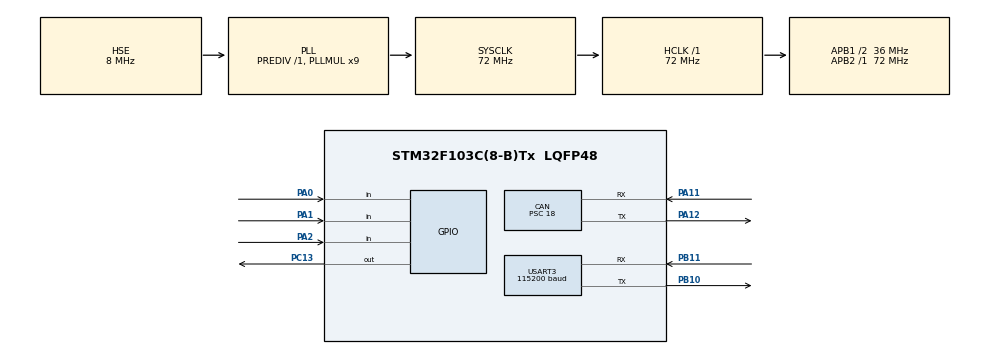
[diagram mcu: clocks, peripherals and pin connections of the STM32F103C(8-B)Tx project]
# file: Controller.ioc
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CAN.BS1=CAN_BS1_2TQ
CAN.CalculateBaudRate=500000
CAN.CalculateTimeBit=2000
CAN.CalculateTimeQuantum=500.0
CAN.Prescaler=18
Mcu.Family=STM32F1
Mcu.Name=STM32F103C(8-B)Tx
Mcu.Package=LQFP48
NVIC.CAN1_RX1_IRQn=true\:2\:0\:true\:false\:true\:true\:true\:true
NVIC.PriorityGroup=NVIC_PRIORITYGROUP_4
NVIC.TIM3_IRQn=true\:1\:0\:true\:false\:true\:true\:true\:true
NVIC.USART3_IRQn=true\:0\:0\:true\:false\:true\:true\:true\:true
NVIC.USB_LP_CAN1_RX0_IRQn=true\:2\:0\:true\:false\:true\:true\:true\:true
PA0-WKUP.GPIO_PuPd=GPIO_PULLUP
PA0-WKUP.Signal=GPIO_Input
PA1.GPIO_PuPd=GPIO_PULLUP
PA1.Signal=GPIO_Input
PA11.Mode=CAN_Activate
PA11.Signal=CAN_RX
PA12.Mode=CAN_Activate
PA12.Signal=CAN_TX
PA13.Mode=Serial_Wire
PA13.Signal=SYS_JTMS-SWDIO
PA14.Mode=Serial_Wire
PA14.Signal=SYS_JTCK-SWCLK
PA2.Signal=GPIO_Input
PB10.Mode=Asynchronous
PB10.Signal=USART3_TX
PB11.Mode=Asynchronous
PB11.Signal=USART3_RX
PC13-TAMPER-RTC.GPIO_PuPd=GPIO_PULLUP
PC13-TAMPER-RTC.Signal=GPIO_Output
PC14-OSC32_IN.Mode=LSE-External-Oscillator
PC14-OSC32_IN.Signal=RCC_OSC32_IN
PC15-OSC32_OUT.Mode=LSE-External-Oscillator
PC15-OSC32_OUT.Signal=RCC_OSC32_OUT
PD0-OSC_IN.Mode=HSE-External-Oscillator
PD0-OSC_IN.Signal=RCC_OSC_IN
PD1-OSC_OUT.Mode=HSE-External-Oscillator
PD1-OSC_OUT.Signal=RCC_OSC_OUT
ProjectManager.HeapSize=0x200
ProjectManager.StackSize=0x400
ProjectManager.TargetToolchain=MDK-ARM V5.32
RCC.AHBFreq_Value=72000000
RCC.APB1CLKDivider=RCC_HCLK_DIV2
RCC.APB1Freq_Value=36000000
RCC.APB1TimFreq_Value=72000000
RCC.APB2Freq_Value=72000000
RCC.APB2TimFreq_Value=72000000
RCC.HCLKFreq_Value=72000000
RCC.PLLMUL=RCC_PLL_MUL9
RCC.PLLSourceVirtual=RCC_PLLSOURCE_HSE
RCC.SYSCLKFreq_VALUE=72000000
RCC.SYSCLKSource=RCC_SYSCLKSOURCE_PLLCLK
RCC.USBFreq_Value=72000000
TIM3.Period=9999
TIM3.Prescaler=1079
USART3.BaudRate=115200
USART3.VirtualMode=VM_ASYNC
VP_TIM3_VS_ClockSourceINT.Mode=Internal
board=custom

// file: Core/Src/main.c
/* USER CODE BEGIN Header */
/**
  ******************************************************************************
  * @file           : main.c
  * @brief          : Main program body
  ******************************************************************************
  * @attention
  *
  * Copyright (c) 2023 STMicroelectronics.
  * All rights reserved.
  *
  * This software is licensed under terms that can be found in the LICENSE file
  * in the root directory of this software component.
  * If no LICENSE file comes with this software, it is provided AS-IS.
  *
  ******************************************************************************
  */
/* USER CODE END Header */
#include "main.h"

/* USER CODE BEGIN Includes */
#include "stdio.h"
#include "convert_lib.h"
/* USER CODE END Includes */

/* USER CODE BEGIN PD */
#define MASTER_ID      			0x281
#define BACK   							0x012
#define FRONT   						0x274
#define BRAKE								0x222
#define ULTRASONIC_ID       0x112

/* USER CODE END PD */

CAN_HandleTypeDef hcan;

TIM_HandleTypeDef htim3;

UART_HandleTypeDef huart3;

/* USER CODE BEGIN PV */
// controller variable

uint32_t back_adc_p = 0;
uint32_t front_adc_p = 0;
uint32_t brake_adc_p = 0;

uint8_t count;
uint8_t buffer;
uint8_t dataBuff[9];
char data_y[20];
char data_v[20];
char data_d[20];
char data_a[20];
char data_us[21];

typedef struct
{
	char Dir;
	uint16_t val;
}dataIn;

dataIn dataInBackWheel;
dataIn dataInFrontWheel;
dataIn dataInBrake;

typedef struct
{
	char type;
	float value;
}dataCAN;

dataCAN dataCANvel = {.type = 'V'};
dataCAN dataCANpos = {.type = 'P'};
dataCAN dataCANyaw = {.type = 'Y'};
dataCAN dataCANangularVel = {.type = 'A'};

typedef struct
{
	char type;
	uint16_t outside;
	uint16_t center;
}ultraSonicDataCAN;

ultraSonicDataCAN ultraSonicLeft = {.type = 'L'};
ultraSonicDataCAN ultraSonicRight = {.type = 'R'};

// CAN protocol variable
CAN_HandleTypeDef     CanHandle;
CAN_TxHeaderTypeDef   TxHeader;
CAN_RxHeaderTypeDef   RxHeader;
uint8_t              	TxBack[8];
uint8_t              	TxFront[8];
uint8_t								TxBrake[8];
uint8_t               RxData[8];
uint32_t              TxMailbox;

/* USER CODE END PV */

void SystemClock_Config(void);
static void MX_GPIO_Init(void);
static void MX_CAN_Init(void);
static void MX_USART3_UART_Init(void);
static void MX_TIM3_Init(void);
/* USER CODE BEGIN PFP */

void WriteCAN(uint16_t ID,uint8_t *data);
void HAL_TIM_PeriodElapsedCallback(TIM_HandleTypeDef *htim);
void HAL_CAN_RxFifo0MsgPendingCallback(CAN_HandleTypeDef *hcan);
void assignUint32_tChar8byte(uint32_t value, char* buffer);
void HAL_UART_RxCpltCallback(UART_HandleTypeDef *huart);
void clearBuffer (uint8_t *buff);
void updateData (uint8_t checkType,uint8_t *data);
void CharToNum (uint16_t *SaveNum, uint8_t *DataIn, uint8_t Index);

/* USER CODE END PFP */

int main(void)
{

  /* MCU Configuration--------------------------------------------------------*/

  /* Reset of all peripherals, Initializes the Flash interface and the Systick. */
  HAL_Init();

  /* Configure the system clock */
  SystemClock_Config();

  /* Initialize all configured peripherals */
  MX_GPIO_Init();
  MX_CAN_Init();
  MX_USART3_UART_Init();
  MX_TIM3_Init();
  /* USER CODE BEGIN 2 */

	HAL_CAN_Start(&hcan);
	HAL_CAN_ActivateNotification(&hcan, CAN_IT_RX_FIFO0_MSG_PENDING);

  TxHeader.DLC = 8;
  TxHeader.ExtId = 0;
  TxHeader.IDE = CAN_ID_STD;
  TxHeader.RTR = CAN_RTR_DATA;
  TxHeader.TransmitGlobalTime = DISABLE;

	HAL_TIM_Base_Start_IT(&htim3);
	HAL_UART_Receive_IT(&huart3, &buffer, 1);

  /* USER CODE END 2 */

  /* Infinite loop */
  while (1)
  {

	}
}

void SystemClock_Config(void)
{
  RCC_OscInitTypeDef RCC_OscInitStruct = {0};
  RCC_ClkInitTypeDef RCC_ClkInitStruct = {0};

  /** Initializes the RCC Oscillators according to the specified parameters
  * in the RCC_OscInitTypeDef structure.
  */
  RCC_OscInitStruct.OscillatorType = RCC_OSCILLATORTYPE_HSE;
  RCC_OscInitStruct.HSEState = RCC_HSE_ON;
  RCC_OscInitStruct.HSEPredivValue = RCC_HSE_PREDIV_DIV1;
  RCC_OscInitStruct.HSIState = RCC_HSI_ON;
  RCC_OscInitStruct.PLL.PLLState = RCC_PLL_ON;
  RCC_OscInitStruct.PLL.PLLSource = RCC_PLLSOURCE_HSE;
  RCC_OscInitStruct.PLL.PLLMUL = RCC_PLL_MUL9;
  if (HAL_RCC_OscConfig(&RCC_OscInitStruct) != HAL_OK)
  {
    Error_Handler();
  }

  /** Initializes the CPU, AHB and APB buses clocks
  */
  RCC_ClkInitStruct.ClockType = RCC_CLOCKTYPE_HCLK|RCC_CLOCKTYPE_SYSCLK
                              |RCC_CLOCKTYPE_PCLK1|RCC_CLOCKTYPE_PCLK2;
  RCC_ClkInitStruct.SYSCLKSource = RCC_SYSCLKSOURCE_PLLCLK;
  RCC_ClkInitStruct.AHBCLKDivider = RCC_SYSCLK_DIV1;
  RCC_ClkInitStruct.APB1CLKDivider = RCC_HCLK_DIV2;
  RCC_ClkInitStruct.APB2CLKDivider = RCC_HCLK_DIV1;

  if (HAL_RCC_ClockConfig(&RCC_ClkInitStruct, FLASH_LATENCY_2) != HAL_OK)
  {
    Error_Handler();
  }
}

static void MX_CAN_Init(void)
{

  hcan.Instance = CAN1;
  hcan.Init.Prescaler = 18;
  hcan.Init.Mode = CAN_MODE_NORMAL;
  hcan.Init.SyncJumpWidth = CAN_SJW_1TQ;
  hcan.Init.TimeSeg1 = CAN_BS1_2TQ;
  hcan.Init.TimeSeg2 = CAN_BS2_1TQ;
  hcan.Init.TimeTriggeredMode = DISABLE;
  hcan.Init.AutoBusOff = DISABLE;
  hcan.Init.AutoWakeUp = DISABLE;
  hcan.Init.AutoRetransmission = DISABLE;
  hcan.Init.ReceiveFifoLocked = DISABLE;
  hcan.Init.TransmitFifoPriority = DISABLE;
  if (HAL_CAN_Init(&hcan) != HAL_OK)
  {
    Error_Handler();
  }
  /* USER CODE BEGIN CAN_Init 2 */
  CAN_FilterTypeDef canfilterconfig;

  canfilterconfig.FilterActivation = CAN_FILTER_ENABLE;
  canfilterconfig.FilterBank = 0;
  canfilterconfig.FilterFIFOAssignment = CAN_RX_FIFO0;
  canfilterconfig.FilterIdHigh = 0x0000;
  canfilterconfig.FilterIdLow = 0x0000;
  canfilterconfig.FilterMaskIdHigh = 0x0000;
  canfilterconfig.FilterMaskIdLow = 0x0000;
  canfilterconfig.FilterMode = CAN_FILTERMODE_IDMASK;
  canfilterconfig.FilterScale = CAN_FILTERSCALE_32BIT;
  canfilterconfig.SlaveStartFilterBank = 13;

  HAL_CAN_ConfigFilter(&hcan, &canfilterconfig);
  /* USER CODE END CAN_Init 2 */

}

static void MX_TIM3_Init(void)
{

  TIM_ClockConfigTypeDef sClockSourceConfig = {0};
  TIM_MasterConfigTypeDef sMasterConfig = {0};

  htim3.Instance = TIM3;
  htim3.Init.Prescaler = 1079;
  htim3.Init.CounterMode = TIM_COUNTERMODE_UP;
  htim3.Init.Period = 9999;
  htim3.Init.ClockDivision = TIM_CLOCKDIVISION_DIV1;
  htim3.Init.AutoReloadPreload = TIM_AUTORELOAD_PRELOAD_DISABLE;
  if (HAL_TIM_Base_Init(&htim3) != HAL_OK)
  {
    Error_Handler();
  }
  sClockSourceConfig.ClockSource = TIM_CLOCKSOURCE_INTERNAL;
  if (HAL_TIM_ConfigClockSource(&htim3, &sClockSourceConfig) != HAL_OK)
  {
    Error_Handler();
  }
  sMasterConfig.MasterOutputTrigger = TIM_TRGO_RESET;
  sMasterConfig.MasterSlaveMode = TIM_MASTERSLAVEMODE_DISABLE;
  if (HAL_TIMEx_MasterConfigSynchronization(&htim3, &sMasterConfig) != HAL_OK)
  {
    Error_Handler();
  }

}

static void MX_USART3_UART_Init(void)
{

  huart3.Instance = USART3;
  huart3.Init.BaudRate = 115200;
  huart3.Init.WordLength = UART_WORDLENGTH_8B;
  huart3.Init.StopBits = UART_STOPBITS_1;
  huart3.Init.Parity = UART_PARITY_NONE;
  huart3.Init.Mode = UART_MODE_TX_RX;
  huart3.Init.HwFlowCtl = UART_HWCONTROL_NONE;
  huart3.Init.OverSampling = UART_OVERSAMPLING_16;
  if (HAL_UART_Init(&huart3) != HAL_OK)
  {
    Error_Handler();
  }

}

static void MX_GPIO_Init(void)
{
  GPIO_InitTypeDef GPIO_InitStruct = {0};

  /* GPIO Ports Clock Enable */
  __HAL_RCC_GPIOC_CLK_ENABLE();
  __HAL_RCC_GPIOD_CLK_ENABLE();
  __HAL_RCC_GPIOA_CLK_ENABLE();
  __HAL_RCC_GPIOB_CLK_ENABLE();

  /*Configure GPIO pin Output Level */
  HAL_GPIO_WritePin(GPIOC, GPIO_PIN_13, GPIO_PIN_RESET);

  /*Configure GPIO pin Output Level */
  HAL_GPIO_WritePin(GPIOA, GPIO_PIN_0|GPIO_PIN_1|GPIO_PIN_2|GPIO_PIN_3
                          |GPIO_PIN_4, GPIO_PIN_RESET);

  /*Configure GPIO pin : PC13 */
  GPIO_InitStruct.Pin = GPIO_PIN_13;
  GPIO_InitStruct.Mode = GPIO_MODE_OUTPUT_PP;
  GPIO_InitStruct.Pull = GPIO_PULLUP;
  GPIO_InitStruct.Speed = GPIO_SPEED_FREQ_LOW;
  HAL_GPIO_Init(GPIOC, &GPIO_InitStruct);

  /*Configure GPIO pins : PA0 PA1 PA2 PA3
                           PA4 */
  GPIO_InitStruct.Pin = GPIO_PIN_0|GPIO_PIN_1|GPIO_PIN_2|GPIO_PIN_3
                          |GPIO_PIN_4;
  GPIO_InitStruct.Mode = GPIO_MODE_OUTPUT_PP;
  GPIO_InitStruct.Pull = GPIO_NOPULL;
  GPIO_InitStruct.Speed = GPIO_SPEED_FREQ_LOW;
  HAL_GPIO_Init(GPIOA, &GPIO_InitStruct);

}

/* USER CODE BEGIN 4 */

void WriteCAN(uint16_t ID,uint8_t *data)
{
	uint8_t dataOut[8];
	TxHeader.StdId = ID;
	dataOut[0] = data[0];
	dataOut[1] = data[1];
	dataOut[2] = data[2];
	dataOut[3] = data[3];
	dataOut[4] = data[4];
	dataOut[5] = data[5];
	dataOut[6] = data[6];
	dataOut[7] = data[7];

	if (HAL_CAN_AddTxMessage(&hcan, &TxHeader, dataOut, &TxMailbox) != HAL_OK)
  {
    Error_Handler();
  }
}
void HAL_CAN_RxFifo0MsgPendingCallback(CAN_HandleTypeDef *hcan)
{
	if(HAL_CAN_GetRxMessage(hcan, CAN_RX_FIFO0, &RxHeader, RxData)== HAL_OK)
	{
		if(RxHeader.StdId==MASTER_ID)
		{

			if(RxData[3]== dataCANvel.type)
			{
				dataCANvel.value = convert8ByteToFloat(RxData,4,7);
				HAL_GPIO_TogglePin(GPIOA, GPIO_PIN_2);
			}

			else if(RxData[3]== dataCANpos.type)
			{
				dataCANpos.value = convert8ByteToFloat(RxData,4,7);
				HAL_GPIO_TogglePin(GPIOA, GPIO_PIN_1);
			}

			else if(RxData[3]== dataCANyaw.type)
			{
				dataCANyaw.value = convert8ByteToFloat(RxData,4,7);
				HAL_GPIO_TogglePin(GPIOA, GPIO_PIN_0);
			}
			else if(RxData[3]== ultraSonicLeft.type)
			{
				ultraSonicLeft.outside = convert8byteToUint16_t(RxData,6,7);
				ultraSonicLeft.center = convert8byteToUint16_t(RxData,4,5);
				HAL_GPIO_TogglePin(GPIOA, GPIO_PIN_3);
			}
			else if(RxData[3]== ultraSonicRight.type)
			{
				ultraSonicRight.outside = convert8byteToUint16_t(RxData,6,7);
				ultraSonicRight.center = convert8byteToUint16_t(RxData,4,5);
				HAL_GPIO_TogglePin(GPIOA, GPIO_PIN_3);
			}
			else if(RxData[3]== dataCANangularVel.type)
			{
				dataCANangularVel.value = convert8ByteToFloat(RxData,4,7);
				HAL_GPIO_TogglePin(GPIOA, GPIO_PIN_4);
			}
		}
	}
}

void HAL_TIM_PeriodElapsedCallback(TIM_HandleTypeDef *htim)
{
  if(htim -> Instance == TIM3){

		sprintf(data_y,"\nY%.1f",dataCANyaw.value);
		HAL_UART_Transmit(&huart3,(uint8_t*)data_y,sizeof(data_y),HAL_MAX_DELAY);

		sprintf(data_d,"\nD%.1f",dataCANpos.value);
		HAL_UART_Transmit(&huart3,(uint8_t*)data_d,sizeof(data_d),HAL_MAX_DELAY);

		sprintf(data_v,"\nV%.1f",dataCANvel.value);
		HAL_UART_Transmit(&huart3,(uint8_t*)data_v,sizeof(data_v),HAL_MAX_DELAY);

		sprintf(data_a,"\nA%.1f",dataCANangularVel.value);
		HAL_UART_Transmit(&huart3,(uint8_t*)data_a,sizeof(data_a),HAL_MAX_DELAY);

		sprintf(data_us,"\nU%d,%d,%d,%d",ultraSonicLeft.outside,ultraSonicLeft.center,ultraSonicRight.center,ultraSonicRight.outside);
		HAL_UART_Transmit(&huart3,(uint8_t*)data_us,sizeof(data_us),HAL_MAX_DELAY);

	}
}

void HAL_UART_RxCpltCallback(UART_HandleTypeDef *huart)
{

	if(huart->Instance == USART3)
	{
		if (buffer != 10)
		{
			dataBuff[count] = buffer;
			count++;
		}
		else if (buffer == 10)
		{
			updateData (dataBuff[0], dataBuff);
			clearBuffer(dataBuff);
		}
		HAL_UART_Receive_IT(&huart3, &buffer, 1);

	}
}

void clearBuffer (uint8_t *buff)
{
	for(int i=0;i<9;i++)
  {
		buff[i]= 0;
  }
	count=0;
}
void updateData (uint8_t checkType, uint8_t *data)
{
	switch (checkType)
  {
  	case 'B':
			dataInBackWheel.Dir = dataBuff[1];
			CharToNum (&dataInBackWheel.val, dataBuff, 2);
			TxBack[6] = dataInBackWheel.Dir;
			TxBack[7] = dataInBackWheel.val;
			WriteCAN(BACK,TxBack);
  		break;
		case 'F':
			CharToNum (&dataInFrontWheel.val, dataBuff, 2);
			TxFront[3] = dataBuff[1];
			convertUint32_tTo8byte(dataInFrontWheel.val,TxFront,4,7);
			WriteCAN(FRONT,TxFront);
  		break;
		case 'P':
			CharToNum (&dataInBrake.val, dataBuff, 1);
  		break;
  }
}

/* USER CODE END 4 */

void Error_Handler(void)
{
  __disable_irq();
  while (1)
  {
  }
}
